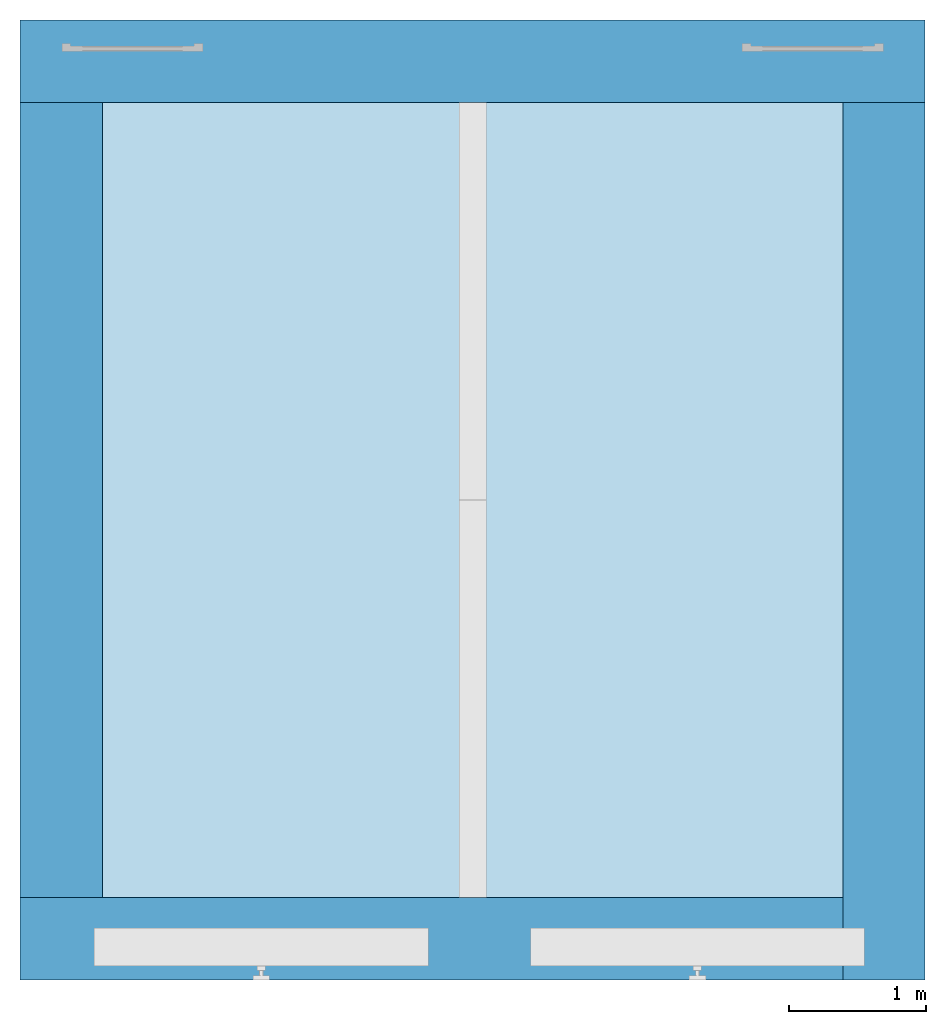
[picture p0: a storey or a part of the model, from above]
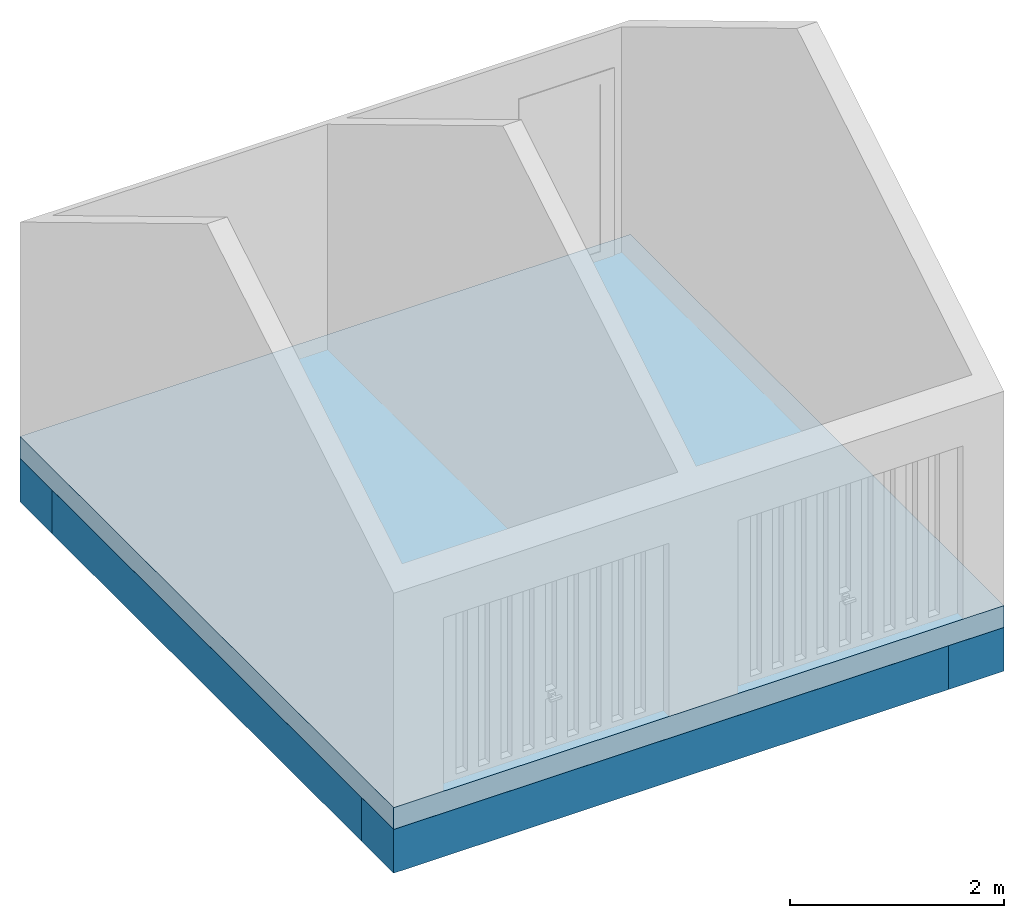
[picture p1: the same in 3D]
Properties of the parts of a building model (IFC2X3)

# File
Description: ViewDefinition [CoordinationView]
Time: 2021-03-24T22:20:31
Made in: SketchUp Pro 2015

# IfcProject, Default Project
Description: Description of Default Project

# IfcSite, Default Site
Description: Description of Object; RefLatitude: 24, 28, 0; RefLongitude: 54, 25, 0; RefElevation: 10 mm

# IfcBuilding, Default Building
Description: Description of Default Building

# IfcBuildingStorey (2)
In: Default Building
Description: Description of Default Building Storey; Elevation: 0 mm
Name
Plan étage
soubassement

# IfcBuildingElementProxy (3)
In: soubassement
Description: Description of Object
Name
2 x 
Object

# IfcDoor (2)
In: soubassement
Description: Description of Object
ObjectType - IfcLabel: 93 x 210 - (90)
PSet_DoorCommon - Reference: 93 x 210 - (90); isExternal: no
Name (IfcDoor - FR_PVC Panneau Plein:93 x 210 - (90):...) | IfcLabel
286378 | FR_PVC Panneau Plein:93 x 210 - (90):286378
286377 | FR_PVC Panneau Plein:93 x 210 - (90):286377

# IfcSlab (3)
Description: Description of Object
PredefinedType - IfcSlabTypeEnum: floor
PSet_SlabCommon - isLoadBearing: yes
Name | In | ObjectType, IfcLabel | Name, IfcLabel | Reference | PitchAngle | isExternal
2 x IfcSlab - Toit de base:Toit - 100 mm 2:286381 | Plan étage | Toit de base:Toit - 100 mm 2 | Toit de base:Toit - 100 mm 2:286381 | Toit - 100 mm 2 | 31 | yes
IfcSlab - Sol:Dalle en béton - 250 mm:286388 | soubassement | Sol:Dalle en béton - 250 mm | Sol:Dalle en béton - 250 mm:286388 | Dalle en béton - 250 mm | 0 | no

# IfcWallStandardCase (4)
In: soubassement
Description: Description of Object
ObjectType - IfcLabel: Mur de base:fond 60 cm:283871
PSet_WallCommon - Reference: fond 60 cm; ExtendToStructure: no; isExternal: yes; isLoadBearing: yes
Name (IfcWallStandardCase - Mur de base:fond 60 cm:...) | IfcLabel
286401 | Mur de base:fond 60 cm:286401
286399 | Mur de base:fond 60 cm:286399
286397 | Mur de base:fond 60 cm:286397
286395 | Mur de base:fond 60 cm:286395
